VERSION 5.7 ;
  NOWIREEXTENSIONATPIN ON ;
  DIVIDERCHAR "/" ;
  BUSBITCHARS "[]" ;
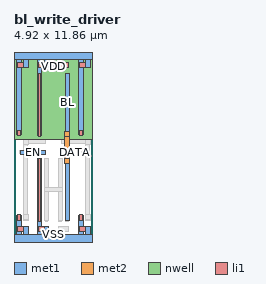
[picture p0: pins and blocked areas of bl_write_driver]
MACRO bl_write_driver
  CLASS BLOCK ;
  FOREIGN bl_write_driver ;
  ORIGIN 0.030 0.000 ;
  SIZE 4.920 BY 11.860 ;
  PIN EN
    DIRECTION INPUT ;
    USE SIGNAL ;
    ANTENNAGATEAREA 0.750000 ;
    PORT
      LAYER met1 ;
        RECT 0.350 5.470 1.930 5.740 ;
    END
  END EN
  PIN DATA
    DIRECTION INPUT ;
    USE SIGNAL ;
    ANTENNAGATEAREA 0.150000 ;
    PORT
      LAYER met1 ;
        RECT 4.220 5.460 4.510 5.750 ;
    END
  END DATA
  PIN BL
    DIRECTION OUTPUT ;
    USE SIGNAL ;
    ANTENNADIFFAREA 2.160000 ;
    PORT
      LAYER met1 ;
        RECT 3.160 6.920 3.430 10.520 ;
        RECT 3.150 6.600 3.440 6.920 ;
        RECT 3.150 4.920 3.440 5.240 ;
        RECT 3.160 1.330 3.430 4.920 ;
      LAYER met2 ;
        RECT 3.150 6.600 3.440 6.920 ;
        RECT 3.150 5.240 3.420 6.600 ;
        RECT 3.150 4.920 3.440 5.240 ;
    END
  END BL
  PIN VDD
    DIRECTION INOUT ;
    USE POWER ;
    ANTENNADIFFAREA 2.481600 ;
    PORT
      LAYER nwell ;
        RECT -0.030 6.400 4.890 11.440 ;
      LAYER li1 ;
        RECT 0.190 10.890 0.800 11.220 ;
        RECT 1.480 10.890 2.090 11.220 ;
        RECT 2.770 10.890 3.380 11.220 ;
        RECT 4.060 10.890 4.670 11.220 ;
        RECT 0.190 6.660 0.360 6.990 ;
        RECT 1.480 6.610 1.650 10.540 ;
        RECT 4.060 6.660 4.230 6.990 ;
      LAYER met1 ;
        RECT 0.000 11.380 4.860 11.860 ;
        RECT 0.140 6.680 0.410 11.380 ;
        RECT 0.580 10.910 0.850 11.380 ;
        RECT 1.430 6.630 1.700 11.380 ;
        RECT 1.870 10.910 2.140 11.380 ;
        RECT 4.010 6.680 4.280 11.380 ;
        RECT 4.450 10.910 4.720 11.380 ;
    END
  END VDD
  PIN VSS
    DIRECTION INOUT ;
    USE GROUND ;
    ANTENNADIFFAREA 2.198700 ;
    PORT
      LAYER li1 ;
        RECT 0.190 1.360 0.360 1.690 ;
        RECT 1.480 1.310 1.650 5.240 ;
        RECT 4.060 1.360 4.230 1.690 ;
        RECT 0.190 0.640 0.800 0.970 ;
        RECT 1.480 0.640 2.090 0.970 ;
        RECT 4.060 0.640 4.670 0.970 ;
      LAYER met1 ;
        RECT 0.140 0.480 0.410 1.670 ;
        RECT 0.580 0.480 0.850 0.950 ;
        RECT 1.430 0.480 1.700 5.220 ;
        RECT 1.870 0.480 2.140 0.950 ;
        RECT 4.010 0.480 4.280 1.670 ;
        RECT 4.450 0.480 4.720 0.950 ;
        RECT 0.000 0.000 4.860 0.480 ;
    END
  END VSS
  OBS
      LAYER li1 ;
        RECT 0.630 6.660 0.800 6.990 ;
        RECT 1.920 6.610 2.090 10.540 ;
        RECT 2.770 6.610 2.940 10.540 ;
        RECT 4.500 6.660 4.670 6.990 ;
        RECT 1.620 6.170 1.950 6.340 ;
        RECT 2.910 6.170 3.240 6.340 ;
        RECT 0.630 1.360 0.800 1.690 ;
        RECT 1.920 1.310 2.090 5.240 ;
        RECT 2.770 1.310 2.940 5.240 ;
        RECT 4.500 1.360 4.670 1.690 ;
        RECT 2.770 0.640 3.380 0.970 ;
        RECT 0.330 5.520 0.660 5.690 ;
        RECT 1.620 5.520 1.950 5.690 ;
        RECT 4.200 5.520 4.530 5.690 ;
        RECT 3.210 6.610 3.380 10.540 ;
        RECT 3.210 1.310 3.380 5.240 ;
      LAYER met1 ;
        RECT 1.870 8.720 2.140 10.520 ;
        RECT 2.720 8.720 2.990 10.520 ;
        RECT 1.870 8.430 2.990 8.720 ;
        RECT 0.580 6.960 0.850 6.980 ;
        RECT 0.570 6.640 0.860 6.960 ;
        RECT 1.870 6.630 2.140 8.430 ;
        RECT 2.720 6.630 2.990 8.430 ;
        RECT 4.450 6.960 4.720 6.980 ;
        RECT 4.440 6.640 4.730 6.960 ;
        RECT 0.570 6.390 0.860 6.400 ;
        RECT 4.440 6.390 4.730 6.400 ;
        RECT 0.570 6.120 1.930 6.390 ;
        RECT 2.930 6.120 4.730 6.390 ;
        RECT 0.570 6.080 0.860 6.120 ;
        RECT 4.440 6.080 4.730 6.120 ;
        RECT 1.870 3.420 2.140 5.220 ;
        RECT 2.720 3.420 2.990 5.220 ;
        RECT 1.870 3.130 2.990 3.420 ;
        RECT 0.570 1.380 0.860 1.700 ;
        RECT 0.580 1.370 0.850 1.380 ;
        RECT 1.870 1.330 2.140 3.130 ;
        RECT 2.720 1.330 2.990 3.130 ;
        RECT 4.440 1.380 4.730 1.700 ;
        RECT 4.450 1.370 4.720 1.380 ;
      LAYER met2 ;
        RECT 0.570 6.640 0.860 6.960 ;
        RECT 4.440 6.640 4.730 6.960 ;
        RECT 0.570 6.400 0.840 6.640 ;
        RECT 4.440 6.400 4.710 6.640 ;
        RECT 0.570 6.080 0.860 6.400 ;
        RECT 4.440 6.080 4.730 6.400 ;
        RECT 0.570 1.700 0.840 6.080 ;
        RECT 4.440 1.700 4.710 6.080 ;
        RECT 0.570 1.380 0.860 1.700 ;
        RECT 4.440 1.380 4.730 1.700 ;
  END
END bl_write_driver
END LIBRARY

